VERSION 5.7 ;
  NOWIREEXTENSIONATPIN ON ;
  DIVIDERCHAR "/" ;
  BUSBITCHARS "[]" ;
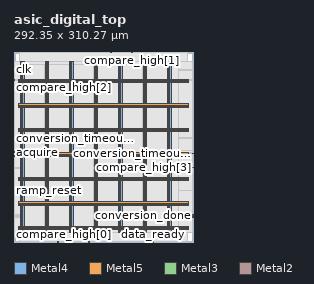
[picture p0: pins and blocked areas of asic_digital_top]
MACRO asic_digital_top
  CLASS BLOCK ;
  FOREIGN asic_digital_top ;
  ORIGIN 0.000 0.000 ;
  SIZE 292.350 BY 310.270 ;
  PIN VDD
    DIRECTION INOUT ;
    USE POWER ;
    PORT
      LAYER Metal4 ;
        RECT 10.720 15.380 12.720 294.300 ;
    END
    PORT
      LAYER Metal4 ;
        RECT 50.720 15.380 52.720 294.300 ;
    END
    PORT
      LAYER Metal4 ;
        RECT 90.720 15.380 92.720 294.300 ;
    END
    PORT
      LAYER Metal4 ;
        RECT 130.720 15.380 132.720 294.300 ;
    END
    PORT
      LAYER Metal4 ;
        RECT 170.720 15.380 172.720 294.300 ;
    END
    PORT
      LAYER Metal4 ;
        RECT 210.720 15.380 212.720 294.300 ;
    END
    PORT
      LAYER Metal4 ;
        RECT 250.720 15.380 252.720 294.300 ;
    END
    PORT
      LAYER Metal5 ;
        RECT 6.720 19.680 285.600 21.680 ;
    END
    PORT
      LAYER Metal5 ;
        RECT 6.720 59.680 285.600 61.680 ;
    END
    PORT
      LAYER Metal5 ;
        RECT 6.720 99.680 285.600 101.680 ;
    END
    PORT
      LAYER Metal5 ;
        RECT 6.720 139.680 285.600 141.680 ;
    END
    PORT
      LAYER Metal5 ;
        RECT 6.720 179.680 285.600 181.680 ;
    END
    PORT
      LAYER Metal5 ;
        RECT 6.720 219.680 285.600 221.680 ;
    END
    PORT
      LAYER Metal5 ;
        RECT 6.720 259.680 285.600 261.680 ;
    END
  END VDD
  PIN VSS
    DIRECTION INOUT ;
    USE GROUND ;
    PORT
      LAYER Metal4 ;
        RECT 14.420 15.380 16.420 294.300 ;
    END
    PORT
      LAYER Metal4 ;
        RECT 54.420 15.380 56.420 294.300 ;
    END
    PORT
      LAYER Metal4 ;
        RECT 94.420 15.380 96.420 294.300 ;
    END
    PORT
      LAYER Metal4 ;
        RECT 134.420 15.380 136.420 294.300 ;
    END
    PORT
      LAYER Metal4 ;
        RECT 174.420 15.380 176.420 294.300 ;
    END
    PORT
      LAYER Metal4 ;
        RECT 214.420 15.380 216.420 294.300 ;
    END
    PORT
      LAYER Metal4 ;
        RECT 254.420 15.380 256.420 294.300 ;
    END
    PORT
      LAYER Metal5 ;
        RECT 6.720 23.380 285.600 25.380 ;
    END
    PORT
      LAYER Metal5 ;
        RECT 6.720 63.380 285.600 65.380 ;
    END
    PORT
      LAYER Metal5 ;
        RECT 6.720 103.380 285.600 105.380 ;
    END
    PORT
      LAYER Metal5 ;
        RECT 6.720 143.380 285.600 145.380 ;
    END
    PORT
      LAYER Metal5 ;
        RECT 6.720 183.380 285.600 185.380 ;
    END
    PORT
      LAYER Metal5 ;
        RECT 6.720 223.380 285.600 225.380 ;
    END
    PORT
      LAYER Metal5 ;
        RECT 6.720 263.380 285.600 265.380 ;
    END
  END VSS
  PIN acquire
    DIRECTION OUTPUT ;
    USE SIGNAL ;
    ANTENNADIFFAREA 1.237600 ;
    PORT
      LAYER Metal3 ;
        RECT 0.000 145.600 0.560 146.160 ;
    END
  END acquire
  PIN clk
    DIRECTION INPUT ;
    USE SIGNAL ;
    ANTENNAGATEAREA 2.352000 ;
    PORT
      LAYER Metal3 ;
        RECT 0.000 281.120 0.560 281.680 ;
    END
  END clk
  PIN compare_high[0]
    DIRECTION INPUT ;
    USE SIGNAL ;
    ANTENNAGATEAREA 2.352000 ;
    PORT
      LAYER Metal2 ;
        RECT 71.680 0.000 72.240 0.560 ;
    END
  END compare_high[0]
  PIN compare_high[1]
    DIRECTION INPUT ;
    USE SIGNAL ;
    ANTENNAGATEAREA 2.352000 ;
    PORT
      LAYER Metal2 ;
        RECT 192.640 309.710 193.200 310.270 ;
    END
  END compare_high[1]
  PIN compare_high[2]
    DIRECTION INPUT ;
    USE SIGNAL ;
    ANTENNAGATEAREA 2.352000 ;
    PORT
      LAYER Metal3 ;
        RECT 0.000 264.320 0.560 264.880 ;
    END
  END compare_high[2]
  PIN compare_high[3]
    DIRECTION INPUT ;
    USE SIGNAL ;
    ANTENNAGATEAREA 2.352000 ;
    PORT
      LAYER Metal3 ;
        RECT 291.790 120.960 292.350 121.520 ;
    END
  END compare_high[3]
  PIN conversion_busy
    DIRECTION OUTPUT ;
    USE SIGNAL ;
    ANTENNADIFFAREA 1.237600 ;
    PORT
      LAYER Metal3 ;
        RECT 0.000 147.840 0.560 148.400 ;
    END
  END conversion_busy
  PIN conversion_done
    DIRECTION OUTPUT ;
    USE SIGNAL ;
    ANTENNADIFFAREA 1.237600 ;
    PORT
      LAYER Metal3 ;
        RECT 291.790 43.680 292.350 44.240 ;
    END
  END conversion_done
  PIN conversion_timeout[0]
    DIRECTION OUTPUT ;
    USE SIGNAL ;
    ANTENNADIFFAREA 1.237600 ;
    PORT
      LAYER Metal2 ;
        RECT 122.080 0.000 122.640 0.560 ;
    END
  END conversion_timeout[0]
  PIN conversion_timeout[1]
    DIRECTION OUTPUT ;
    USE SIGNAL ;
    ANTENNADIFFAREA 1.237600 ;
    PORT
      LAYER Metal2 ;
        RECT 157.920 309.710 158.480 310.270 ;
    END
  END conversion_timeout[1]
  PIN conversion_timeout[2]
    DIRECTION OUTPUT ;
    USE SIGNAL ;
    ANTENNADIFFAREA 1.237600 ;
    PORT
      LAYER Metal3 ;
        RECT 0.000 169.120 0.560 169.680 ;
    END
  END conversion_timeout[2]
  PIN conversion_timeout[3]
    DIRECTION OUTPUT ;
    USE SIGNAL ;
    ANTENNADIFFAREA 1.237600 ;
    PORT
      LAYER Metal3 ;
        RECT 291.790 144.480 292.350 145.040 ;
    END
  END conversion_timeout[3]
  PIN data_ready
    DIRECTION OUTPUT ;
    USE SIGNAL ;
    ANTENNADIFFAREA 1.237600 ;
    PORT
      LAYER Metal2 ;
        RECT 227.360 0.000 227.920 0.560 ;
    END
  END data_ready
  PIN ramp_connect
    DIRECTION OUTPUT ;
    USE SIGNAL ;
    ANTENNADIFFAREA 1.237600 ;
    PORT
      LAYER Metal3 ;
        RECT 0.000 146.720 0.560 147.280 ;
    END
  END ramp_connect
  PIN ramp_reset
    DIRECTION OUTPUT ;
    USE SIGNAL ;
    ANTENNADIFFAREA 1.237600 ;
    PORT
      LAYER Metal3 ;
        RECT 0.000 84.000 0.560 84.560 ;
    END
  END ramp_reset
  PIN rst_n
    DIRECTION INPUT ;
    USE SIGNAL ;
    ANTENNAGATEAREA 1.999200 ;
    PORT
      LAYER Metal3 ;
        RECT 291.790 40.320 292.350 40.880 ;
    END
  END rst_n
  PIN serial_data
    DIRECTION OUTPUT ;
    USE SIGNAL ;
    ANTENNADIFFAREA 1.237600 ;
    PORT
      LAYER Metal2 ;
        RECT 225.120 0.000 225.680 0.560 ;
    END
  END serial_data
  PIN shift_en
    DIRECTION INPUT ;
    USE SIGNAL ;
    ANTENNAGATEAREA 0.666400 ;
    PORT
      LAYER Metal2 ;
        RECT 226.240 0.000 226.800 0.560 ;
    END
  END shift_en
  PIN start
    DIRECTION INPUT ;
    USE SIGNAL ;
    ANTENNAGATEAREA 0.666400 ;
    PORT
      LAYER Metal3 ;
        RECT 0.000 140.000 0.560 140.560 ;
    END
  END start
  OBS
      LAYER Nwell ;
        RECT 6.290 15.250 286.030 294.430 ;
      LAYER Metal1 ;
        RECT 6.720 15.380 285.600 294.300 ;
      LAYER Metal2 ;
        RECT 9.100 309.410 157.620 309.710 ;
        RECT 158.780 309.410 192.340 309.710 ;
        RECT 193.500 309.410 284.060 309.710 ;
        RECT 9.100 0.860 284.060 309.410 ;
        RECT 9.100 0.560 71.380 0.860 ;
        RECT 72.540 0.560 121.780 0.860 ;
        RECT 122.940 0.560 224.820 0.860 ;
        RECT 228.220 0.560 284.060 0.860 ;
      LAYER Metal3 ;
        RECT 0.560 281.980 292.180 294.140 ;
        RECT 0.860 280.820 292.180 281.980 ;
        RECT 0.560 265.180 292.180 280.820 ;
        RECT 0.860 264.020 292.180 265.180 ;
        RECT 0.560 169.980 292.180 264.020 ;
        RECT 0.860 168.820 292.180 169.980 ;
        RECT 0.560 148.700 292.180 168.820 ;
        RECT 0.860 145.340 292.180 148.700 ;
        RECT 0.860 145.300 291.490 145.340 ;
        RECT 0.560 144.180 291.490 145.300 ;
        RECT 0.560 140.860 292.180 144.180 ;
        RECT 0.860 139.700 292.180 140.860 ;
        RECT 0.560 121.820 292.180 139.700 ;
        RECT 0.560 120.660 291.490 121.820 ;
        RECT 0.560 84.860 292.180 120.660 ;
        RECT 0.860 83.700 292.180 84.860 ;
        RECT 0.560 44.540 292.180 83.700 ;
        RECT 0.560 43.380 291.490 44.540 ;
        RECT 0.560 41.180 292.180 43.380 ;
        RECT 0.560 40.020 291.490 41.180 ;
        RECT 0.560 14.700 292.180 40.020 ;
      LAYER Metal4 ;
        RECT 16.940 20.250 50.420 289.430 ;
        RECT 53.020 20.250 54.120 289.430 ;
        RECT 56.720 20.250 90.420 289.430 ;
        RECT 93.020 20.250 94.120 289.430 ;
        RECT 96.720 20.250 130.420 289.430 ;
        RECT 133.020 20.250 134.120 289.430 ;
        RECT 136.720 20.250 170.420 289.430 ;
        RECT 173.020 20.250 174.120 289.430 ;
        RECT 176.720 20.250 210.420 289.430 ;
        RECT 213.020 20.250 214.120 289.430 ;
        RECT 216.720 20.250 250.420 289.430 ;
        RECT 253.020 20.250 254.120 289.430 ;
        RECT 256.720 20.250 268.660 289.430 ;
  END
END asic_digital_top
END LIBRARY

